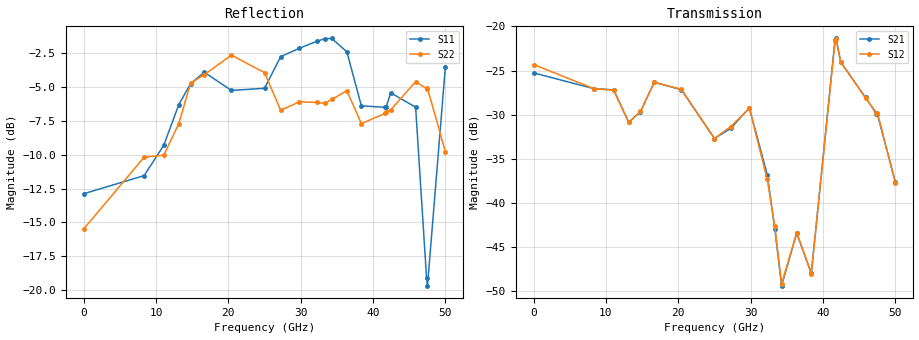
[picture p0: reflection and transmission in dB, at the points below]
!Keysight Technologies,N5245B,MY58422270,A.16.20.02
!Date: Thursday, March 05, 2026 01:32:11
!Correction: S11(C  2-Port  )
!S21(C  2-Port  )
!S12(C  2-Port  )
!S22(C  2-Port  )
!S2P File: Measurements: S11, S21, S12, S22:
# Hz S  dB  R 50
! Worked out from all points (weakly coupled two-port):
!   3201 points, 10 MHz to 50 GHz, reference 50 ohm
!   highest |S21| = -21.35 dB at 41.81 GHz (marker M1); lowest = -49.4 dB at 34.28 GHz (marker M2)
!   lowest |S11| = -19.7 dB at 47.53 GHz (marker M3), VSWR 1.23, Z = 45.9 + j9.12 ohm
!   |S11| at or under -10 dB: start of sweep to 10.08 GHz; 11.36 GHz to 11.92 GHz (560.9 MHz wide, 4.82 % of centre); 46.66 GHz to 48.28 GHz (1.616 GHz wide, 3.4 % of centre)
!   |S22| runs from -20.0 to -2.6 dB; largest |S21 - S12| = 0.0066
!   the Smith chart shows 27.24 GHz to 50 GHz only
!   S11 on the Smith chart (normalised r, x): 27.24 GHz: 0.18, +0.37; 32.3 GHz: 0.42, +1.86; 36.38 GHz: 2.36, -3.33; 42.45 GHz: 0.99, -1.26; 47.41 GHz: 0.84, +0.13; 50 GHz: 0.62, -1.35
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1e7  -12.88 -2.9  -25.27 3.6  -24.32 5.4  -15.48 40.9
8.352081e9  -11.54 175.0  -27.06 28.9  -27.06 28.7  -10.18 -178.5
1.107029e10  -9.30 109.7  -27.20 -71.6  -27.23 -72.0  -10.03 82.9
1.3148e10  -6.29 64.7  -30.88 -127.5  -30.88 -127.6  -7.70 -24.1
1.477267e10  -4.74 12.8  -29.67 -149.6  -29.65 -149.9  -4.71 -91.3
1.667854e10  -3.90 -43.8  -26.33 158.9  -26.34 158.7  -4.07 -141.1
2.042779e10  -5.24 -122.0  -27.18 38.8  -27.13 39.0  -2.63 154.8
2.5005e10  -5.08 179.9  -32.72 -65.5  -32.72 -65.4  -3.93 71.6
2.723893e10  -2.74 138.6  -31.57 -114.4  -31.36 -114.7  -6.71 31.5
2.983216e10  -2.12 93.7  -29.24 158.8  -29.30 159.0  -6.08 -28.8
3.230042e10  -1.59 54.8  -36.81 46.1  -37.33 45.7  -6.13 -103.6
3.334708e10  -1.42 36.0  -42.99 1.0  -42.68 2.2  -6.20 -126.6
3.428439e10  -1.39 19.4  -49.42 -82.8  -49.20 -87.3  -5.91 -146.2
3.637772e10  -2.38 -23.0  -43.46 117.7  -43.39 118.7  -5.26 173.6
3.839295e10  -6.38 -22.4  -48.02 -104.2  -48.07 -119.8  -7.69 141.5
4.167354e10  -6.49 -52.6  -21.54 -54.5  -21.64 -54.9  -6.94 115.4
4.181414e10  -6.47 -52.5  -21.35 -67.8  -21.42 -67.9  -6.81 114.0
4.245463e10  -5.42 -57.9  -24.03 -114.1  -24.03 -115.1  -6.68 109.9
4.589145e10  -6.48 -117.1  -28.06 51.3  -28.13 50.0  -4.59 62.8
4.740677e10  -19.13 137.5  -29.93 -2.9  -29.79 -4.0  -5.11 43.3
4.753174e10  -19.68 108.6  -29.97 -5.3  -29.77 -5.0  -5.08 41.9
5e10  -3.53 -66.0  -37.61 -140.0  -37.76 -145.4  -9.76 4.2
